One B-rep face of a CAD part: STEP entity #127.
In plain terms, the planar face has unit normal (0, 0, 1).
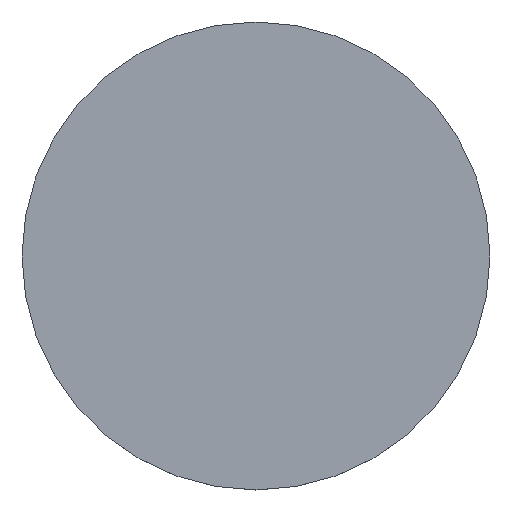
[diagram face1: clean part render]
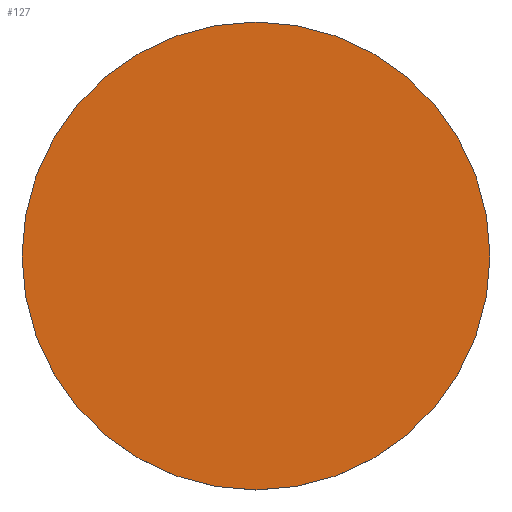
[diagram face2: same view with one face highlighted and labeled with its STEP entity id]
Its self-contained STEP definition (entity closure, numbers rounded to 3 decimals):
#42 = VERTEX_POINT('',#43);
#43 = CARTESIAN_POINT('',(0.5,0.,0.035));
#50 = CYLINDRICAL_SURFACE('',#51,0.5);
#51 = AXIS2_PLACEMENT_3D('',#52,#53,#54);
#52 = CARTESIAN_POINT('',(0.,0.,0.));
#53 = DIRECTION('',(-0.,-0.,-1.));
#54 = DIRECTION('',(1.,0.,0.));
#69 = EDGE_CURVE('',#42,#42,#70,.T.);
#70 = SURFACE_CURVE('',#71,(#76,#83),.PCURVE_S1.);
#71 = CIRCLE('',#72,0.5);
#72 = AXIS2_PLACEMENT_3D('',#73,#74,#75);
#73 = CARTESIAN_POINT('',(0.,0.,0.035));
#74 = DIRECTION('',(0.,0.,1.));
#75 = DIRECTION('',(1.,0.,0.));
#76 = PCURVE('',#50,#77);
#77 = DEFINITIONAL_REPRESENTATION('',(#78),#82);
#78 = LINE('',#79,#80);
#79 = CARTESIAN_POINT('',(-0.,-0.035));
#80 = VECTOR('',#81,1.);
#81 = DIRECTION('',(-1.,0.));
#82 = ( GEOMETRIC_REPRESENTATION_CONTEXT(2) 
PARAMETRIC_REPRESENTATION_CONTEXT() REPRESENTATION_CONTEXT('2D SPACE',''
  ) );
#83 = PCURVE('',#84,#89);
#84 = PLANE('',#85);
#85 = AXIS2_PLACEMENT_3D('',#86,#87,#88);
#86 = CARTESIAN_POINT('',(0.,0.,0.035)
  );
#87 = DIRECTION('',(0.,0.,1.));
#88 = DIRECTION('',(1.,0.,-0.));
#89 = DEFINITIONAL_REPRESENTATION('',(#90),#94);
#90 = CIRCLE('',#91,0.5);
#91 = AXIS2_PLACEMENT_2D('',#92,#93);
#92 = CARTESIAN_POINT('',(0.,0.));
#93 = DIRECTION('',(1.,0.));
#94 = ( GEOMETRIC_REPRESENTATION_CONTEXT(2) 
PARAMETRIC_REPRESENTATION_CONTEXT() REPRESENTATION_CONTEXT('2D SPACE',''
  ) );
#127 = ADVANCED_FACE('',(#128),#84,.T.);
#128 = FACE_BOUND('',#129,.T.);
#129 = EDGE_LOOP('',(#130));
#130 = ORIENTED_EDGE('',*,*,#69,.T.);
